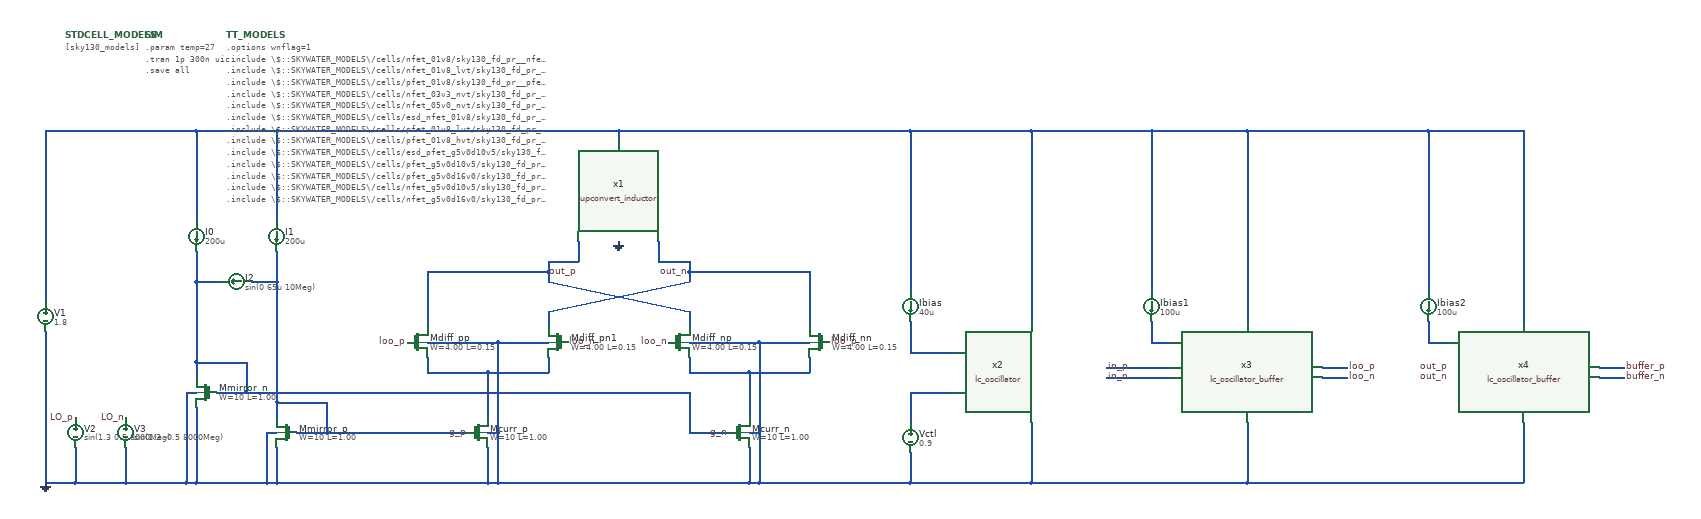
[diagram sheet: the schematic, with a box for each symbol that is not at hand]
v {xschem version=2.9.9 file_version=1.2 }
G {}
K {}
V {}
S {}
E {}
N 760 -250 760 -220 { lab=#net1}
N 880 -220 1000 -220 { lab=#net1}
N 1000 -250 1000 -220 { lab=#net1}
N 880 -220 880 -130 { lab=#net1}
N 900 -280 1000 -280 { lab=GND}
N 900 -100 900 -0 { lab=GND}
N 880 -70 880 0 { lab=GND}
N 880 -100 900 -100 { lab=GND}
N 1280 -250 1280 -220 { lab=#net2}
N 1400 -220 1520 -220 { lab=#net2}
N 1520 -250 1520 -220 { lab=#net2}
N 1400 -220 1400 -130 { lab=#net2}
N 1420 -280 1520 -280 { lab=GND}
N 1420 -100 1420 0 { lab=GND}
N 1400 -70 1400 0 { lab=GND}
N 1400 -100 1420 -100 { lab=GND}
N 560 -100 840 -100 { lab=g_p}
N 440 -100 460 -100 { lab=GND}
N 440 -100 440 -0 { lab=GND}
N 460 -70 460 0 { lab=GND}
N 460 -160 460 -130 { lab=g_p}
N 460 -160 560 -160 { lab=g_p}
N 560 -160 560 -100 { lab=g_p}
N 400 -180 1280 -180 { lab=g_n}
N 1280 -180 1280 -100 { lab=g_n}
N 1280 -100 1360 -100 { lab=g_n}
N 300 -240 300 -210 { lab=g_n}
N 300 -240 400 -240 { lab=g_n}
N 400 -240 400 -180 { lab=g_n}
N 300 -150 300 0 { lab=GND}
N 280 -180 300 -180 { lab=GND}
N 280 -180 280 -0 { lab=GND}
N 1400 0 1420 0 { lab=GND}
N 1000 -340 1000 -310 { lab=out_n}
N 1280 -340 1280 -310 { lab=out_p}
N 460 -400 460 -160 { lab=g_p}
N 300 -400 300 -240 { lab=g_n}
N 300 -460 300 -400 { lab=g_n}
N 1520 -420 1520 -310 { lab=out_n}
N 760 -420 760 -310 { lab=out_p}
N 1000 -340 1280 -400 { lab=out_n}
N 1000 -400 1280 -340 { lab=out_p}
N 1280 -420 1280 -400 { lab=out_n}
N 1000 -420 1000 -400 { lab=out_p}
N 0 -300 -0 -0 { lab=GND}
N 160 0 280 -0 { lab=GND}
N 410 -400 460 -400 { lab=g_p}
N 300 -400 350 -400 { lab=g_n}
N 60 -70 60 -0 { lab=GND}
N 160 -70 160 0 { lab=GND}
N 760 -220 880 -220 { lab=#net1}
N 760 -280 900 -280 { lab=GND}
N 880 0 900 -0 { lab=GND}
N 460 0 880 0 { lab=GND}
N 900 -280 900 -100 { lab=GND}
N 1280 -220 1400 -220 { lab=#net2}
N 1280 -280 1420 -280 { lab=GND}
N 900 -0 1400 0 { lab=GND}
N 1420 -280 1420 -100 { lab=GND}
N 300 0 440 -0 { lab=GND}
N 440 -0 460 0 { lab=GND}
N 500 -100 560 -100 { lab=g_p}
N 340 -180 400 -180 { lab=g_n}
N 280 -0 300 0 { lab=GND}
N 1280 -420 1520 -420 { lab=out_n}
N 460 -460 460 -400 { lab=g_p}
N -0 -0 60 -0 { lab=GND}
N 60 -0 160 0 { lab=GND}
N 460 -700 460 -520 { lab=#net3}
N 300 -700 300 -520 { lab=#net3}
N 760 -420 1000 -420 { lab=out_p}
N 1140 -700 1140 -680 { lab=#net3}
N 1220 -480 1220 -440 { lab=out_n}
N 1220 -440 1280 -440 { lab=out_n}
N 1280 -440 1280 -420 { lab=out_n}
N 1060 -480 1060 -440 { lab=out_p}
N 1000 -440 1060 -440 { lab=out_p}
N 1000 -440 1000 -420 { lab=out_p}
N -0 -700 -0 -360 { lab=#net3}
N 300 -700 460 -700 { lab=#net3}
N -0 -700 300 -700 { lab=#net3}
N 460 -700 1140 -700 { lab=#net3}
N 1960 -700 1960 -320 { lab=#net3}
N 1720 -700 1960 -700 { lab=#net3}
N 2110 -210 2240 -210 { lab=in_n}
N 2110 -230 2240 -230 { lab=in_p}
N 1960 -120 1960 0 { lab=GND}
N 1720 -60 1720 0 { lab=GND}
N 1720 -180 1720 -120 { lab=#net4}
N 1720 -180 1810 -180 { lab=#net4}
N 1720 -700 1720 -380 { lab=#net3}
N 1720 -320 1720 -260 { lab=#net5}
N 1720 -260 1810 -260 { lab=#net5}
N 2390 -120 2390 0 { lab=GND}
N 2200 -280 2240 -280 { lab=#net6}
N 2200 -320 2200 -280 { lab=#net6}
N 2200 -700 2200 -380 { lab=#net3}
N 2390 -700 2390 -320 { lab=#net3}
N 1720 0 1960 0 { lab=GND}
N 1960 0 2390 0 { lab=GND}
N 1960 -700 2200 -700 { lab=#net3}
N 1420 0 1720 0 { lab=GND}
N 1140 -700 1720 -700 { lab=#net3}
N 2540 -230 2590 -230 { lab=loo_p}
N 2540 -210 2590 -210 { lab=loo_n}
N 2200 -700 2390 -700 { lab=#net3}
N 2940 -120 2940 0 { lab=GND}
N 2750 -280 2790 -280 { lab=#net7}
N 2750 -320 2750 -280 { lab=#net7}
N 2750 -700 2750 -380 { lab=#net3}
N 2940 -700 2940 -320 { lab=#net3}
N 3090 -230 3140 -230 { lab=buffer_p}
N 3090 -210 3140 -210 { lab=buffer_n}
N 2750 -700 2940 -700 { lab=#net3}
N 2390 0 2940 0 { lab=GND}
N 2390 -700 2750 -700 { lab=#net3}
C {sky130_fd_pr/nfet_01v8_lvt.sym} 860 -100 0 0 {name=Mcurr_p
L=1.00
W=10
nf=2
mult=8
ad="'int((nf+1)/2) * W/nf * 0.29'" 
pd="'2*int((nf+1)/2) * (W/nf + 0.29)'"
as="'int((nf+2)/2) * W/nf * 0.29'" 
ps="'2*int((nf+2)/2) * (W/nf + 0.29)'"
nrd="'0.29 / W'" nrs="'0.29 / W'"
sa=0 sb=0 sd=0
model=nfet_01v8_lvt
spiceprefix=X
}
C {sky130_fd_pr/nfet_01v8_lvt.sym} 740 -280 0 0 {name=Mdiff_pp
L=0.15
W=4.00
nf=1
mult=2
ad="'int((nf+1)/2) * W/nf * 0.29'" 
pd="'2*int((nf+1)/2) * (W/nf + 0.29)'"
as="'int((nf+2)/2) * W/nf * 0.29'" 
ps="'2*int((nf+2)/2) * (W/nf + 0.29)'"
nrd="'0.29 / W'" nrs="'0.29 / W'"
sa=0 sb=0 sd=0
model=nfet_01v8_lvt
spiceprefix=X
}
C {sky130_fd_pr/nfet_01v8_lvt.sym} 1020 -280 0 1 {name=Mdiff_pn1
L=0.15
W=4.00
nf=1
mult=2
ad="'int((nf+1)/2) * W/nf * 0.29'" 
pd="'2*int((nf+1)/2) * (W/nf + 0.29)'"
as="'int((nf+2)/2) * W/nf * 0.29'" 
ps="'2*int((nf+2)/2) * (W/nf + 0.29)'"
nrd="'0.29 / W'" nrs="'0.29 / W'"
sa=0 sb=0 sd=0
model=nfet_01v8_lvt
spiceprefix=X
}
C {sky130_fd_pr/nfet_01v8_lvt.sym} 1380 -100 0 0 {name=Mcurr_n
L=1.00
W=10
nf=2
mult=8
ad="'int((nf+1)/2) * W/nf * 0.29'" 
pd="'2*int((nf+1)/2) * (W/nf + 0.29)'"
as="'int((nf+2)/2) * W/nf * 0.29'" 
ps="'2*int((nf+2)/2) * (W/nf + 0.29)'"
nrd="'0.29 / W'" nrs="'0.29 / W'"
sa=0 sb=0 sd=0
model=nfet_01v8_lvt
spiceprefix=X
}
C {sky130_fd_pr/nfet_01v8_lvt.sym} 1260 -280 0 0 {name=Mdiff_np
L=0.15
W=4.00
nf=1
mult=2
ad="'int((nf+1)/2) * W/nf * 0.29'" 
pd="'2*int((nf+1)/2) * (W/nf + 0.29)'"
as="'int((nf+2)/2) * W/nf * 0.29'" 
ps="'2*int((nf+2)/2) * (W/nf + 0.29)'"
nrd="'0.29 / W'" nrs="'0.29 / W'"
sa=0 sb=0 sd=0
model=nfet_01v8_lvt
spiceprefix=X
}
C {sky130_fd_pr/nfet_01v8_lvt.sym} 1540 -280 0 1 {name=Mdiff_nn
L=0.15
W=4.00
nf=1
mult=2
ad="'int((nf+1)/2) * W/nf * 0.29'" 
pd="'2*int((nf+1)/2) * (W/nf + 0.29)'"
as="'int((nf+2)/2) * W/nf * 0.29'" 
ps="'2*int((nf+2)/2) * (W/nf + 0.29)'"
nrd="'0.29 / W'" nrs="'0.29 / W'"
sa=0 sb=0 sd=0
model=nfet_01v8_lvt
spiceprefix=X
}
C {sky130_fd_pr/nfet_01v8_lvt.sym} 320 -180 0 1 {name=Mmirror_n
L=1.00
W=10
nf=2
mult=2
ad="'int((nf+1)/2) * W/nf * 0.29'" 
pd="'2*int((nf+1)/2) * (W/nf + 0.29)'"
as="'int((nf+2)/2) * W/nf * 0.29'" 
ps="'2*int((nf+2)/2) * (W/nf + 0.29)'"
nrd="'0.29 / W'" nrs="'0.29 / W'"
sa=0 sb=0 sd=0
model=nfet_01v8_lvt
spiceprefix=X
}
C {sky130_fd_pr/nfet_01v8_lvt.sym} 480 -100 0 1 {name=Mmirror_p
L=1.00
W=10
nf=2
mult=2
ad="'int((nf+1)/2) * W/nf * 0.29'" 
pd="'2*int((nf+1)/2) * (W/nf + 0.29)'"
as="'int((nf+2)/2) * W/nf * 0.29'" 
ps="'2*int((nf+2)/2) * (W/nf + 0.29)'"
nrd="'0.29 / W'" nrs="'0.29 / W'"
sa=0 sb=0 sd=0
model=nfet_01v8_lvt
spiceprefix=X
}
C {vsource.sym} 0 -330 0 0 {name=V1 value=1.8}
C {gnd.sym} 0 0 0 0 {name=l5 lab=GND}
C {lab_pin.sym} 1000 -420 0 1 {name=l6 sig_type=std_logic lab=out_p}
C {lab_pin.sym} 1280 -420 0 0 {name=l7 sig_type=std_logic lab=out_n}
C {isource.sym} 300 -490 0 0 {name=I0 value=200u}
C {isource.sym} 460 -490 0 0 {name=I1 value=200u}
C {isource.sym} 380 -400 1 0 {name=I2 value="sin(0 65u 10Meg)"}
C {code.sym} 200 -890 0 0 {name=SIM only_toplevel=false value="
.param temp=27

.tran 1p 300n uic

.save all

"}
C {devices/code.sym} 360 -890 0 0 {name=TT_MODELS
only_toplevel=true
format="tcleval( @value )"
value="
.options wnflag=1
.include \\\\$::SKYWATER_MODELS\\\\/cells/nfet_01v8/sky130_fd_pr__nfet_01v8__tt.corner.spice
.include \\\\$::SKYWATER_MODELS\\\\/cells/nfet_01v8_lvt/sky130_fd_pr__nfet_01v8_lvt__tt.corner.spice
.include \\\\$::SKYWATER_MODELS\\\\/cells/pfet_01v8/sky130_fd_pr__pfet_01v8__tt.corner.spice
.include \\\\$::SKYWATER_MODELS\\\\/cells/nfet_03v3_nvt/sky130_fd_pr__nfet_03v3_nvt__tt.corner.spice
.include \\\\$::SKYWATER_MODELS\\\\/cells/nfet_05v0_nvt/sky130_fd_pr__nfet_05v0_nvt__tt.corner.spice
.include \\\\$::SKYWATER_MODELS\\\\/cells/esd_nfet_01v8/sky130_fd_pr__esd_nfet_01v8__tt.corner.spice
.include \\\\$::SKYWATER_MODELS\\\\/cells/pfet_01v8_lvt/sky130_fd_pr__pfet_01v8_lvt__tt.corner.spice
.include \\\\$::SKYWATER_MODELS\\\\/cells/pfet_01v8_hvt/sky130_fd_pr__pfet_01v8_hvt__tt.corner.spice
.include \\\\$::SKYWATER_MODELS\\\\/cells/esd_pfet_g5v0d10v5/sky130_fd_pr__esd_pfet_g5v0d10v5__tt.corner.spice
.include \\\\$::SKYWATER_MODELS\\\\/cells/pfet_g5v0d10v5/sky130_fd_pr__pfet_g5v0d10v5__tt.corner.spice
.include \\\\$::SKYWATER_MODELS\\\\/cells/pfet_g5v0d16v0/sky130_fd_pr__pfet_g5v0d16v0__tt.corner.spice
.include \\\\$::SKYWATER_MODELS\\\\/cells/nfet_g5v0d10v5/sky130_fd_pr__nfet_g5v0d10v5__tt.corner.spice
.include \\\\$::SKYWATER_MODELS\\\\/cells/nfet_g5v0d16v0/sky130_fd_pr__nfet_g5v0d16v0__tt_discrete.corner.spice
.include \\\\$::SKYWATER_MODELS\\\\/cells/esd_nfet_g5v0d10v5/sky130_fd_pr__esd_nfet_g5v0d10v5__tt.corner.spice
.include \\\\$::SKYWATER_MODELS\\\\/models/corners/tt/nonfet.spice
* Mismatch parameters
.include \\\\$::SKYWATER_MODELS\\\\/cells/nfet_01v8/sky130_fd_pr__nfet_01v8__mismatch.corner.spice
.include \\\\$::SKYWATER_MODELS\\\\/cells/pfet_01v8/sky130_fd_pr__pfet_01v8__mismatch.corner.spice
.include \\\\$::SKYWATER_MODELS\\\\/cells/nfet_01v8_lvt/sky130_fd_pr__nfet_01v8_lvt__mismatch.corner.spice
.include \\\\$::SKYWATER_MODELS\\\\/cells/pfet_01v8_lvt/sky130_fd_pr__pfet_01v8_lvt__mismatch.corner.spice
.include \\\\$::SKYWATER_MODELS\\\\/cells/pfet_01v8_hvt/sky130_fd_pr__pfet_01v8_hvt__mismatch.corner.spice
.include \\\\$::SKYWATER_MODELS\\\\/cells/nfet_g5v0d10v5/sky130_fd_pr__nfet_g5v0d10v5__mismatch.corner.spice
.include \\\\$::SKYWATER_MODELS\\\\/cells/pfet_g5v0d10v5/sky130_fd_pr__pfet_g5v0d10v5__mismatch.corner.spice
.include \\\\$::SKYWATER_MODELS\\\\/cells/nfet_05v0_nvt/sky130_fd_pr__nfet_05v0_nvt__mismatch.corner.spice
.include \\\\$::SKYWATER_MODELS\\\\/cells/nfet_03v3_nvt/sky130_fd_pr__nfet_03v3_nvt__mismatch.corner.spice
* Resistor\\\\$::SKYWATER_MODELS\\\\/Capacitor
.include \\\\$::SKYWATER_MODELS\\\\/models/r+c/res_typical__cap_typical.spice
.include \\\\$::SKYWATER_MODELS\\\\/models/r+c/res_typical__cap_typical__lin.spice
* Special cells
.include \\\\$::SKYWATER_MODELS\\\\/models/corners/tt/specialized_cells.spice
* All models
.include \\\\$::SKYWATER_MODELS\\\\/models/all.spice
* Corner
.include \\\\$::SKYWATER_MODELS\\\\/models/corners/tt/rf.spice
"}
C {code.sym} 40 -890 0 0 {name=STDCELL_MODELS
only_toplevel=true
format="tcleval( @value )"
value="[sky130_models]"
}
C {vsource.sym} 60 -100 0 0 {name=V2 value="sin(1.3 0.5 8000Meg)"}
C {vsource.sym} 160 -100 0 0 {name=V3 value="sin(1.3 -0.5 8000Meg)"}
C {lab_pin.sym} 60 -130 0 0 {name=l8 sig_type=std_logic lab=LO_p}
C {lab_pin.sym} 160 -130 0 0 {name=l9 sig_type=std_logic lab=LO_n}
C {lab_wire.sym} 840 -100 0 0 {name=l11 sig_type=std_logic lab=g_p}
C {lab_wire.sym} 1360 -100 0 0 {name=l10 sig_type=std_logic lab=g_n}
C {upconvert_inductor/upconvert_inductor.sym} 1140 -580 0 0 {name=x1}
C {gnd.sym} 1140 -480 0 0 {name=l12 lab=GND}
C {lc_oscillator/lc_oscillator.sym} 1960 -220 0 0 {name=x2}
C {isource.sym} 1720 -350 0 0 {name=Ibias value=40u}
C {vsource.sym} 1720 -90 0 0 {name=Vctl value=0.9}
C {lab_wire.sym} 2110 -230 0 1 {name=l13 sig_type=std_logic lab=in_p}
C {lab_wire.sym} 2110 -210 0 1 {name=l14 sig_type=std_logic lab=in_n}
C {lc_oscillator_buffer/lc_oscillator_buffer.sym} 2390 -220 0 0 {name=x3}
C {lab_wire.sym} 2590 -230 0 1 {name=l15 sig_type=std_logic lab=loo_p}
C {lab_wire.sym} 2590 -210 0 1 {name=l16 sig_type=std_logic lab=loo_n}
C {isource.sym} 2200 -350 0 0 {name=Ibias1 value=100u}
C {lab_wire.sym} 1040 -280 0 1 {name=l1 sig_type=std_logic lab=loo_n}
C {lab_wire.sym} 1240 -280 0 0 {name=l3 sig_type=std_logic lab=loo_n}
C {lab_wire.sym} 1560 -280 0 1 {name=l4 sig_type=std_logic lab=loo_p}
C {lab_wire.sym} 720 -280 0 0 {name=l2 sig_type=std_logic lab=loo_p}
C {lc_oscillator_buffer/lc_oscillator_buffer.sym} 2940 -220 0 0 {name=x4}
C {lab_wire.sym} 3140 -230 0 1 {name=l17 sig_type=std_logic lab=buffer_p}
C {lab_wire.sym} 3140 -210 0 1 {name=l18 sig_type=std_logic lab=buffer_n}
C {isource.sym} 2750 -350 0 0 {name=Ibias2 value=100u}
C {lab_pin.sym} 2790 -230 0 0 {name=l19 sig_type=std_logic lab=out_p}
C {lab_pin.sym} 2790 -210 0 0 {name=l20 sig_type=std_logic lab=out_n}
